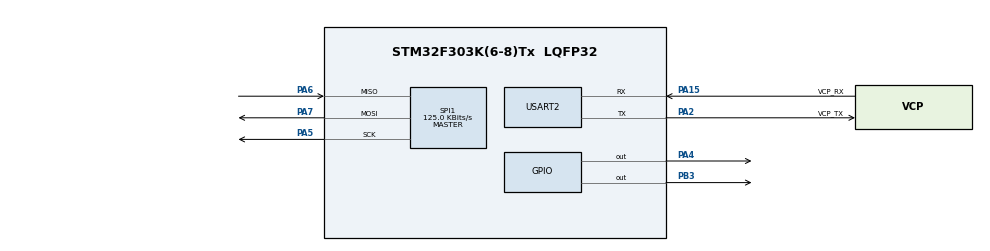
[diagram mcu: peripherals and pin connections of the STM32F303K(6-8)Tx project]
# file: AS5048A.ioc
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Mcu.Family=STM32F3
Mcu.Name=STM32F303K(6-8)Tx
Mcu.Package=LQFP32
NVIC.PriorityGroup=NVIC_PRIORITYGROUP_4
NVIC.TIM1_UP_TIM16_IRQn=true\:0\:0\:false\:false\:true\:true\:true\:true
PA13.GPIO_Label=SWDIO
PA13.Mode=Serial_Wire
PA13.Signal=SYS_JTMS-SWDIO
PA14.GPIO_Label=SWCLK
PA14.Mode=Serial_Wire
PA14.Signal=SYS_JTCK-SWCLK
PA15.GPIO_Label=VCP_RX
PA15.Mode=Asynchronous
PA15.Signal=USART2_RX
PA2.GPIO_Label=VCP_TX
PA2.Mode=Asynchronous
PA2.Signal=USART2_TX
PA4.Signal=GPIO_Output
PA5.Mode=Full_Duplex_Master
PA5.Signal=SPI1_SCK
PA6.Mode=Full_Duplex_Master
PA6.Signal=SPI1_MISO
PA7.Mode=Full_Duplex_Master
PA7.Signal=SPI1_MOSI
PB3.Signal=GPIO_Output
PF0\ /\ OSC_IN.GPIO_Label=MCO
PF0\ /\ OSC_IN.Mode=HSE-External-Clock-Source
PF0\ /\ OSC_IN.Signal=RCC_OSC_IN
ProjectManager.HeapSize=0x200
ProjectManager.StackSize=0x400
ProjectManager.TargetToolchain=STM32CubeIDE
RCC.AHBCLKDivider=RCC_SYSCLK_DIV2
RCC.AHBFreq_Value=8000000
RCC.APB1CLKDivider=RCC_HCLK_DIV2
RCC.APB1Freq_Value=4000000
RCC.APB1TimFreq_Value=8000000
RCC.APB2Freq_Value=8000000
RCC.APB2TimFreq_Value=8000000
RCC.CortexFreq_Value=8000000
RCC.HCLKFreq_Value=8000000
RCC.HSE_VALUE=8000000
RCC.HSI_VALUE=8000000
RCC.PLLSourceVirtual=RCC_PLLSOURCE_HSE
RCC.SYSCLKFreq_VALUE=16000000
RCC.SYSCLKSourceVirtual=RCC_SYSCLKSOURCE_PLLCLK
SPI1.BaudRatePrescaler=SPI_BAUDRATEPRESCALER_64
SPI1.CLKPhase=SPI_PHASE_1EDGE
SPI1.CLKPolarity=SPI_POLARITY_LOW
SPI1.CalculateBaudRate=125.0 KBits/s
SPI1.DataSize=SPI_DATASIZE_16BIT
SPI1.Direction=SPI_DIRECTION_2LINES
SPI1.Mode=SPI_MODE_MASTER
SPI1.VirtualType=VM_MASTER
TIM1.Period=1000-1
TIM1.Prescaler=8-1
USART2.VirtualMode-Asynchronous=VM_ASYNC
VP_TIM1_VS_ClockSourceINT.Mode=Internal
board=NUCLEO-F303K8

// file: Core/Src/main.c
/* USER CODE BEGIN Header */
/**
  ******************************************************************************
  * @file           : main.c
  * @brief          : Main program body
  ******************************************************************************
  * @attention
  *
  * Copyright (c) 2023 STMicroelectronics.
  * All rights reserved.
  *
  * This software is licensed under terms that can be found in the LICENSE file
  * in the root directory of this software component.
  * If no LICENSE file comes with this software, it is provided AS-IS.
  *
  ******************************************************************************
  */
/* USER CODE END Header */
#include "main.h"
#include "spi.h"
#include "tim.h"
#include "usart.h"
#include "gpio.h"

/* USER CODE BEGIN Includes */
#include <stdio.h>
#include <stdint.h>
#include <stdbool.h>
#include <string.h>
/* USER CODE END Includes */

void SystemClock_Config(void);

/* USER CODE BEGIN 0 */
int cnt = 0;

//void HAL_TIM_PeriodElapsedCallback(TIM_HandleTypeDef *htim)
//{
//    if (htim == &htim1) // interruption 1kHz
//    {
//    	cnt = (cnt + 1) % 1000;
//    	if(cnt == 999){
//    		HAL_GPIO_WritePin(GPIOB, GPIO_PIN_3, GPIO_PIN_SET);
//    	}
//    	else{
//    		HAL_GPIO_WritePin(GPIOB, GPIO_PIN_3, GPIO_PIN_RESET);
//    	}

//    	if(cnt == 200){
//    		printf("Hello!\n");
//    	}
//    }
// }
/* USER CODE END 0 */

int main(void)
{

  /* MCU Configuration--------------------------------------------------------*/

  /* Reset of all peripherals, Initializes the Flash interface and the Systick. */
  HAL_Init();

  /* Configure the system clock */
  SystemClock_Config();

  /* Initialize all configured peripherals */
  MX_GPIO_Init();
  MX_USART2_UART_Init();
  MX_SPI1_Init();
  MX_TIM1_Init();
  /* USER CODE BEGIN 2 */
//  HAL_TIM_Base_Start_IT(&htim1);
  setbuf(stdout, NULL);
  printf("Hello\n");
  /* USER CODE END 2 */

  /* Infinite loop */
  while (1)
  {

    /* USER CODE BEGIN 3 */
	  HAL_GPIO_WritePin(GPIOB, GPIO_PIN_3, GPIO_PIN_SET);
	  HAL_GPIO_WritePin(GPIOA, GPIO_PIN_4, GPIO_PIN_SET);
  }
  /* USER CODE END 3 */
}

void SystemClock_Config(void)
{
  RCC_OscInitTypeDef RCC_OscInitStruct = {0};
  RCC_ClkInitTypeDef RCC_ClkInitStruct = {0};
  RCC_PeriphCLKInitTypeDef PeriphClkInit = {0};

  /** Initializes the RCC Oscillators according to the specified parameters
  * in the RCC_OscInitTypeDef structure.
  */
  RCC_OscInitStruct.OscillatorType = RCC_OSCILLATORTYPE_HSE;
  RCC_OscInitStruct.HSEState = RCC_HSE_BYPASS;
  RCC_OscInitStruct.HSEPredivValue = RCC_HSE_PREDIV_DIV1;
  RCC_OscInitStruct.HSIState = RCC_HSI_ON;
  RCC_OscInitStruct.PLL.PLLState = RCC_PLL_ON;
  RCC_OscInitStruct.PLL.PLLSource = RCC_PLLSOURCE_HSE;
  RCC_OscInitStruct.PLL.PLLMUL = RCC_PLL_MUL9;
  if (HAL_RCC_OscConfig(&RCC_OscInitStruct) != HAL_OK)
  {
    Error_Handler();
  }
  /** Initializes the CPU, AHB and APB buses clocks
  */
  RCC_ClkInitStruct.ClockType = RCC_CLOCKTYPE_HCLK|RCC_CLOCKTYPE_SYSCLK
                              |RCC_CLOCKTYPE_PCLK1|RCC_CLOCKTYPE_PCLK2;
  RCC_ClkInitStruct.SYSCLKSource = RCC_SYSCLKSOURCE_PLLCLK;
  RCC_ClkInitStruct.AHBCLKDivider = RCC_SYSCLK_DIV1;
  RCC_ClkInitStruct.APB1CLKDivider = RCC_HCLK_DIV2;
  RCC_ClkInitStruct.APB2CLKDivider = RCC_HCLK_DIV1;

  if (HAL_RCC_ClockConfig(&RCC_ClkInitStruct, FLASH_LATENCY_2) != HAL_OK)
  {
    Error_Handler();
  }
  PeriphClkInit.PeriphClockSelection = RCC_PERIPHCLK_TIM1;
  PeriphClkInit.Tim1ClockSelection = RCC_TIM1CLK_HCLK;
  if (HAL_RCCEx_PeriphCLKConfig(&PeriphClkInit) != HAL_OK)
  {
    Error_Handler();
  }
}

void Error_Handler(void)
{
  __disable_irq();
  while (1)
  {
  }
}
